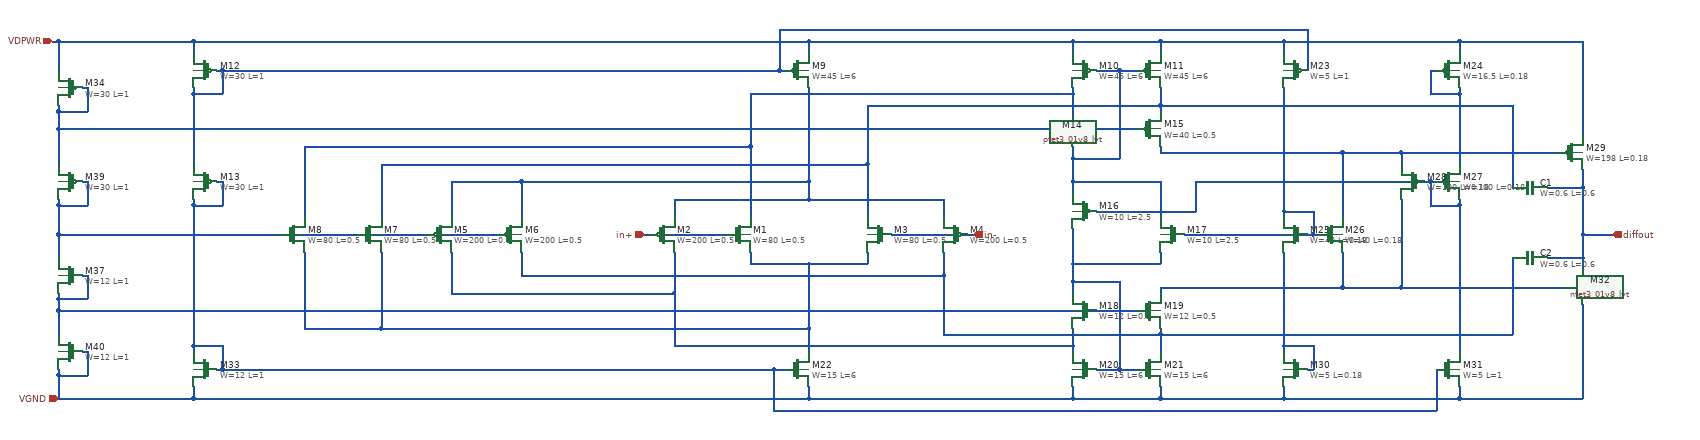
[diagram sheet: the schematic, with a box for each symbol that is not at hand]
v {xschem version=3.4.5 file_version=1.2
}
G {}
K {}
V {}
S {}
E {}
N -230 -60 -230 -30 {
lab=#net1}
N 0 -60 230 -60 {
lab=#net1}
N 230 -60 230 -30 {
lab=#net1}
N 0 -90 0 -60 {
lab=#net1}
N -490 -90 0 -90 {
lab=#net1}
N -490 -90 -490 -30 {
lab=#net1}
N -610 -90 -490 -90 {
lab=#net1}
N -610 -90 -610 -30 {
lab=#net1}
N -100 -150 -100 -30 {
lab=#net2}
N -860 -150 -100 -150 {
lab=#net2}
N -860 -150 -860 -30 {
lab=#net2}
N -730 -120 -730 -30 {
lab=#net3}
N -730 -120 100 -120 {
lab=#net3}
N 100 -120 100 -30 {
lab=#net3}
N -100 30 -100 50 {
lab=#net4}
N 0 50 0 160 {
lab=#net4}
N -730 160 0 160 {
lab=#net4}
N -730 30 -730 160 {
lab=#net4}
N -280 0 -140 0 {
lab=in+}
N -490 70 230 70 {
lab=#net5}
N 230 70 230 170 {
lab=#net5}
N -610 30 -610 100 {
lab=#net6}
N -610 100 -230 100 {
lab=#net6}
N -230 30 -230 100 {
lab=#net6}
N 0 -250 0 -90 {
lab=#net1}
N -1050 -250 -1050 -240 {
lab=#net7}
N -1050 -240 -1000 -240 {
lab=#net7}
N -1000 -280 -1000 -240 {
lab=#net7}
N -1050 -240 -1050 -120 {
lab=#net7}
N 530 -280 560 -280 {
lab=#net8}
N 450 -240 450 -200 {
lab=#net2}
N 600 -220 600 -210 {
lab=#net3}
N 450 -130 450 -90 {
lab=#net8}
N 530 -280 530 -130 {
lab=#net8}
N 450 50 450 80 {
lab=#net9}
N 450 -10 450 50 {
lab=#net9}
N 450 -90 600 -90 {
lab=#net8}
N 600 -90 600 -30 {
lab=#net8}
N 450 80 450 100 {
lab=#net9}
N 450 80 530 80 {
lab=#net9}
N 530 230 560 230 {
lab=#net9}
N 450 190 450 200 {
lab=#net6}
N 600 170 600 200 {
lab=#net5}
N 530 80 530 230 {
lab=#net9}
N 0 160 0 200 {
lab=#net4}
N 0 260 0 280 {
lab=VGND}
N 450 280 600 280 {
lab=VGND}
N 600 260 600 280 {
lab=VGND}
N 450 260 450 280 {
lab=VGND}
N 450 -330 450 -310 {
lab=VDPWR}
N 450 -330 600 -330 {
lab=VDPWR}
N 600 -330 600 -310 {
lab=VDPWR}
N 600 -330 810 -330 {
lab=VDPWR}
N 810 -330 810 -310 {
lab=VDPWR}
N 810 -330 1110 -330 {
lab=VDPWR}
N 1060 -280 1070 -280 {
lab=#net10}
N 1060 -280 1060 -240 {
lab=#net10}
N 1060 -240 1110 -240 {
lab=#net10}
N 1110 -250 1110 -240 {
lab=#net10}
N 810 -250 810 -40 {
lab=#net11}
N 860 0 870 0 {
lab=#net11}
N 860 -40 860 0 {
lab=#net11}
N 810 -40 860 -40 {
lab=#net11}
N 1060 -90 1070 -90 {
lab=#net12}
N 1110 -240 1110 -120 {
lab=#net10}
N 1060 -90 1060 -50 {
lab=#net12}
N 1060 -50 1110 -50 {
lab=#net12}
N 1110 -60 1110 -50 {
lab=#net12}
N 450 -130 530 -130 {
lab=#net8}
N 450 -90 450 -70 {
lab=#net8}
N 1110 -330 1110 -310 {
lab=VDPWR}
N 600 -150 600 -140 {
lab=#net13}
N 1010 -140 1280 -140 {
lab=#net13}
N -230 -60 0 -60 {
lab=#net1}
N -100 50 0 50 {
lab=#net4}
N -1010 -280 -1000 -280 {
lab=#net7}
N 490 -280 530 -280 {
lab=#net8}
N 490 230 530 230 {
lab=#net9}
N 0 280 450 280 {
lab=VGND}
N 450 -150 450 -130 {
lab=#net8}
N 810 -40 810 -30 {
lab=#net11}
N 600 30 600 50 {
lab=#net9}
N 450 50 600 50 {
lab=#net9}
N 490 -40 660 -40 {
lab=#net12}
N 660 -90 660 -40 {
lab=#net12}
N 640 0 860 0 {
lab=#net11}
N 660 -90 1060 -90 {
lab=#net12}
N 810 190 810 200 {
lab=#net14}
N 600 280 810 280 {
lab=VGND}
N 810 260 810 280 {
lab=VGND}
N 1110 -50 1110 200 {
lab=#net12}
N 1110 280 1320 280 {
lab=VGND}
N 1320 120 1320 280 {
lab=VGND}
N 1010 90 1290 90 {
lab=#net15}
N 1320 40 1320 60 {
lab=diffout}
N 1320 -330 1320 -170 {
lab=VDPWR}
N 1110 -330 1320 -330 {
lab=VDPWR}
N 1110 260 1110 280 {
lab=VGND}
N 1070 230 1070 300 {
lab=#net16}
N -60 300 1070 300 {
lab=#net16}
N -60 230 -60 300 {
lab=#net16}
N -60 230 -40 230 {
lab=#net16}
N -1000 230 -60 230 {
lab=#net16}
N -1050 260 -1050 280 {
lab=VGND}
N -1050 280 0 280 {
lab=VGND}
N -1000 190 -1000 230 {
lab=#net16}
N -1050 190 -1000 190 {
lab=#net16}
N -1050 190 -1050 200 {
lab=#net16}
N -1280 280 -1050 280 {
lab=VGND}
N 850 -350 850 -280 {
lab=#net7}
N -50 -350 850 -350 {
lab=#net7}
N 0 -330 0 -310 {
lab=VDPWR}
N 0 -330 450 -330 {
lab=VDPWR}
N -50 -350 -50 -280 {
lab=#net7}
N -50 -280 -40 -280 {
lab=#net7}
N -1050 -330 0 -330 {
lab=VDPWR}
N -1280 -330 -1280 -280 {
lab=VDPWR}
N -1050 -330 -1050 -310 {
lab=VDPWR}
N -1050 -50 -1000 -50 {
lab=#net16}
N -1000 -90 -1000 -50 {
lab=#net16}
N -1010 -90 -1000 -90 {
lab=#net16}
N 600 90 600 100 {
lab=#net15}
N 600 90 910 90 {
lab=#net15}
N 910 30 910 90 {
lab=#net15}
N 1010 -60 1010 90 {
lab=#net15}
N 850 230 860 230 {
lab=#net14}
N 860 190 860 230 {
lab=#net14}
N 810 190 860 190 {
lab=#net14}
N 600 170 1200 170 {
lab=#net5}
N 600 -220 1200 -220 {
lab=#net3}
N 1010 -140 1010 -120 {
lab=#net13}
N 910 -140 910 -30 {
lab=#net13}
N 140 0 280 0 {
lab=in-}
N 100 -220 100 -120 {
lab=#net3}
N 100 -220 600 -220 {
lab=#net3}
N -100 -240 -100 -150 {
lab=#net2}
N -100 -240 450 -240 {
lab=#net2}
N -230 100 -230 190 {
lab=#net6}
N -230 190 450 190 {
lab=#net6}
N -1280 -180 560 -180 {
lab=#net17}
N -1280 0 -530 0 {
lab=#net18}
N -1280 130 560 130 {
lab=#net19}
N 0 50 100 50 {
lab=#net4}
N 100 30 100 50 {
lab=#net4}
N -490 30 -490 70 {
lab=#net5}
N 230 30 230 70 {
lab=#net5}
N 810 280 1110 280 {
lab=VGND}
N -1010 230 -1000 230 {
lab=#net16}
N -1050 -50 -1050 190 {
lab=#net16}
N -1280 -330 -1050 -330 {
lab=VDPWR}
N -1050 -60 -1050 -50 {
lab=#net16}
N 910 90 1010 90 {
lab=#net15}
N 810 30 810 190 {
lab=#net14}
N 600 160 600 170 {
lab=#net5}
N 600 -250 600 -220 {
lab=#net3}
N 910 -140 1010 -140 {
lab=#net13}
N 600 -140 910 -140 {
lab=#net13}
N 450 -250 450 -240 {
lab=#net2}
N 450 160 450 190 {
lab=#net6}
N -860 30 -860 160 {
lab=#net4}
N -860 160 -730 160 {
lab=#net4}
N 1200 40 1200 170 {
lab=#net5}
N 1260 40 1320 40 {
lab=diffout}
N 1200 -220 1200 -80 {
lab=#net3}
N 1260 -80 1320 -80 {
lab=diffout}
N 1320 0 1370 0 {
lab=diffout}
N -1290 -330 -1280 -330 {
lab=VDPWR}
N -1000 -280 -50 -280 {
lab=#net7}
N -1240 -250 -1230 -250 {
lab=#net17}
N -1230 -250 -1230 -210 {
lab=#net17}
N -1280 -210 -1230 -210 {
lab=#net17}
N -1280 -220 -1280 -210 {
lab=#net17}
N -1280 -210 -1280 -180 {
lab=#net17}
N -1280 -180 -1280 -120 {
lab=#net17}
N -1240 -90 -1230 -90 {
lab=#net18}
N -1230 -90 -1230 -50 {
lab=#net18}
N -1280 -50 -1230 -50 {
lab=#net18}
N -1280 -60 -1280 -50 {
lab=#net18}
N -1280 -50 -1280 0 {
lab=#net18}
N -1240 70 -1230 70 {
lab=#net19}
N -1230 70 -1230 110 {
lab=#net19}
N -1280 110 -1230 110 {
lab=#net19}
N -1280 100 -1280 110 {
lab=#net19}
N -1280 0 -1280 40 {
lab=#net18}
N -1280 110 -1280 130 {
lab=#net19}
N -1240 200 -1230 200 {
lab=VGND}
N -1230 200 -1230 240 {
lab=VGND}
N -1280 240 -1230 240 {
lab=VGND}
N -1280 230 -1280 240 {
lab=VGND}
N -1280 130 -1280 170 {
lab=#net19}
N -1280 240 -1280 280 {
lab=VGND}
N 1320 0 1320 40 {
lab=diffout}
N 1320 -110 1320 -80 {
lab=diffout}
N 1320 -80 1320 0 {
lab=diffout}
N 230 170 600 170 {
lab=#net5}
C {sky130_fd_pr/nfet3_01v8_lvt.sym} -120 0 0 0 {name=M1
L=0.5
W=80
nf=4
mult=1
body=GND
ad="'int((nf+1)/2) * W/nf * 0.29'" 
pd="'2*int((nf+1)/2) * (W/nf + 0.29)'"
as="'int((nf+2)/2) * W/nf * 0.29'" 
ps="'2*int((nf+2)/2) * (W/nf + 0.29)'"
nrd="'0.29 / W'" nrs="'0.29 / W'"
sa=0 sb=0 sd=0
model=nfet_01v8_lvt
spiceprefix=X
}
C {sky130_fd_pr/pfet3_01v8_lvt.sym} -250 0 0 0 {name=M2
L=0.5
W=200
body=VDD
nf=6
mult=1
ad="'int((nf+1)/2) * W/nf * 0.29'" 
pd="'2*int((nf+1)/2) * (W/nf + 0.29)'"
as="'int((nf+2)/2) * W/nf * 0.29'" 
ps="'2*int((nf+2)/2) * (W/nf + 0.29)'"
nrd="'0.29 / W'" nrs="'0.29 / W'"
sa=0 sb=0 sd=0
model=pfet_01v8_lvt
spiceprefix=X
}
C {sky130_fd_pr/nfet3_01v8_lvt.sym} 120 0 0 1 {name=M3
L=0.5
W=80
nf=4
mult=1
body=GND
ad="'int((nf+1)/2) * W/nf * 0.29'" 
pd="'2*int((nf+1)/2) * (W/nf + 0.29)'"
as="'int((nf+2)/2) * W/nf * 0.29'" 
ps="'2*int((nf+2)/2) * (W/nf + 0.29)'"
nrd="'0.29 / W'" nrs="'0.29 / W'"
sa=0 sb=0 sd=0
model=nfet_01v8_lvt
spiceprefix=X
}
C {sky130_fd_pr/pfet3_01v8_lvt.sym} 250 0 0 1 {name=M4
L=0.5
W=200
body=VDD
nf=6
mult=1
ad="'int((nf+1)/2) * W/nf * 0.29'" 
pd="'2*int((nf+1)/2) * (W/nf + 0.29)'"
as="'int((nf+2)/2) * W/nf * 0.29'" 
ps="'2*int((nf+2)/2) * (W/nf + 0.29)'"
nrd="'0.29 / W'" nrs="'0.29 / W'"
sa=0 sb=0 sd=0
model=pfet_01v8_lvt
spiceprefix=X
}
C {sky130_fd_pr/pfet3_01v8_lvt.sym} -630 0 0 0 {name=M5
L=0.5
W=200
body=VDD
nf=6
mult=1
ad="'int((nf+1)/2) * W/nf * 0.29'" 
pd="'2*int((nf+1)/2) * (W/nf + 0.29)'"
as="'int((nf+2)/2) * W/nf * 0.29'" 
ps="'2*int((nf+2)/2) * (W/nf + 0.29)'"
nrd="'0.29 / W'" nrs="'0.29 / W'"
sa=0 sb=0 sd=0
model=pfet_01v8_lvt
spiceprefix=X
}
C {sky130_fd_pr/pfet3_01v8_lvt.sym} -510 0 0 0 {name=M6
L=0.5
W=200
body=VDD
nf=6
mult=1
ad="'int((nf+1)/2) * W/nf * 0.29'" 
pd="'2*int((nf+1)/2) * (W/nf + 0.29)'"
as="'int((nf+2)/2) * W/nf * 0.29'" 
ps="'2*int((nf+2)/2) * (W/nf + 0.29)'"
nrd="'0.29 / W'" nrs="'0.29 / W'"
sa=0 sb=0 sd=0
model=pfet_01v8_lvt
spiceprefix=X
}
C {sky130_fd_pr/nfet3_01v8_lvt.sym} -750 0 0 0 {name=M7
L=0.5
W=80
nf=1
mult=1
body=GND
ad="'int((nf+1)/2) * W/nf * 0.29'" 
pd="'2*int((nf+1)/2) * (W/nf + 0.29)'"
as="'int((nf+2)/2) * W/nf * 0.29'" 
ps="'2*int((nf+2)/2) * (W/nf + 0.29)'"
nrd="'0.29 / W'" nrs="'0.29 / W'"
sa=0 sb=0 sd=0
model=nfet_01v8_lvt
spiceprefix=X
}
C {sky130_fd_pr/nfet3_01v8_lvt.sym} -880 0 0 0 {name=M8
L=0.5
W=80
nf=1
mult=1
body=GND
ad="'int((nf+1)/2) * W/nf * 0.29'" 
pd="'2*int((nf+1)/2) * (W/nf + 0.29)'"
as="'int((nf+2)/2) * W/nf * 0.29'" 
ps="'2*int((nf+2)/2) * (W/nf + 0.29)'"
nrd="'0.29 / W'" nrs="'0.29 / W'"
sa=0 sb=0 sd=0
model=nfet_01v8_lvt
spiceprefix=X
}
C {devices/ipin.sym} -280 0 0 0 {name=p1 lab=in+}
C {devices/ipin.sym} 280 0 0 1 {name=p2 lab=in-

}
C {sky130_fd_pr/pfet3_01v8_lvt.sym} -20 -280 0 0 {name=M9
L=6
W=45
body=VDD
nf=1
mult=1
ad="'int((nf+1)/2) * W/nf * 0.29'" 
pd="'2*int((nf+1)/2) * (W/nf + 0.29)'"
as="'int((nf+2)/2) * W/nf * 0.29'" 
ps="'2*int((nf+2)/2) * (W/nf + 0.29)'"
nrd="'0.29 / W'" nrs="'0.29 / W'"
sa=0 sb=0 sd=0
model=pfet_01v8_lvt
spiceprefix=X
}
C {sky130_fd_pr/pfet3_01v8_lvt.sym} -1030 -280 0 1 {name=M12
L=1
W=30
body=VDD
nf=1
mult=1
ad="'int((nf+1)/2) * W/nf * 0.29'" 
pd="'2*int((nf+1)/2) * (W/nf + 0.29)'"
as="'int((nf+2)/2) * W/nf * 0.29'" 
ps="'2*int((nf+2)/2) * (W/nf + 0.29)'"
nrd="'0.29 / W'" nrs="'0.29 / W'"
sa=0 sb=0 sd=0
model=pfet_01v8_lvt
spiceprefix=X
}
C {sky130_fd_pr/pfet3_01v8_lvt.sym} -1030 -90 0 1 {name=M13
L=1
W=30
body=VDD
nf=1
mult=1
ad="'int((nf+1)/2) * W/nf * 0.29'" 
pd="'2*int((nf+1)/2) * (W/nf + 0.29)'"
as="'int((nf+2)/2) * W/nf * 0.29'" 
ps="'2*int((nf+2)/2) * (W/nf + 0.29)'"
nrd="'0.29 / W'" nrs="'0.29 / W'"
sa=0 sb=0 sd=0
model=pfet_01v8_lvt
spiceprefix=X
}
C {sky130_fd_pr/pfet3_01v8_lvt.sym} 470 -280 0 1 {name=M10
L=6
W=45
body=VDD
nf=1
mult=1
ad="'int((nf+1)/2) * W/nf * 0.29'" 
pd="'2*int((nf+1)/2) * (W/nf + 0.29)'"
as="'int((nf+2)/2) * W/nf * 0.29'" 
ps="'2*int((nf+2)/2) * (W/nf + 0.29)'"
nrd="'0.29 / W'" nrs="'0.29 / W'"
sa=0 sb=0 sd=0
model=pfet_01v8_lvt
spiceprefix=X
}
C {sky130_fd_pr/pfet3_01v8_lvt.sym} 580 -280 0 0 {name=M11
L=6
W=45
body=VDD
nf=1
mult=1
ad="'int((nf+1)/2) * W/nf * 0.29'" 
pd="'2*int((nf+1)/2) * (W/nf + 0.29)'"
as="'int((nf+2)/2) * W/nf * 0.29'" 
ps="'2*int((nf+2)/2) * (W/nf + 0.29)'"
nrd="'0.29 / W'" nrs="'0.29 / W'"
sa=0 sb=0 sd=0
model=pfet_01v8_lvt
spiceprefix=X
}
C {sky130_fd_pr/pfet3_01v8_lvt.sym} 470 -180 0 1 {name=M14
L=0.5
W=40
body=VDD
nf=1
mult=1
ad="'int((nf+1)/2) * W/nf * 0.29'" 
pd="'2*int((nf+1)/2) * (W/nf + 0.29)'"
as="'int((nf+2)/2) * W/nf * 0.29'" 
ps="'2*int((nf+2)/2) * (W/nf + 0.29)'"
nrd="'0.29 / W'" nrs="'0.29 / W'"
sa=0 sb=0 sd=0
model=pfet_01v8_lvt
spiceprefix=X
}
C {sky130_fd_pr/pfet3_01v8_lvt.sym} 580 -180 0 0 {name=M15
L=0.5
W=40
body=VDD
nf=1
mult=1
ad="'int((nf+1)/2) * W/nf * 0.29'" 
pd="'2*int((nf+1)/2) * (W/nf + 0.29)'"
as="'int((nf+2)/2) * W/nf * 0.29'" 
ps="'2*int((nf+2)/2) * (W/nf + 0.29)'"
nrd="'0.29 / W'" nrs="'0.29 / W'"
sa=0 sb=0 sd=0
model=pfet_01v8_lvt
spiceprefix=X
}
C {sky130_fd_pr/pfet3_01v8_lvt.sym} 470 -40 0 1 {name=M16
L=2.5
W=10
body=VDD
nf=1
mult=1
ad="'int((nf+1)/2) * W/nf * 0.29'" 
pd="'2*int((nf+1)/2) * (W/nf + 0.29)'"
as="'int((nf+2)/2) * W/nf * 0.29'" 
ps="'2*int((nf+2)/2) * (W/nf + 0.29)'"
nrd="'0.29 / W'" nrs="'0.29 / W'"
sa=0 sb=0 sd=0
model=pfet_01v8_lvt
spiceprefix=X
}
C {sky130_fd_pr/nfet3_01v8_lvt.sym} 620 0 0 1 {name=M17
L=2.5
W=10
nf=1
mult=1
body=GND
ad="'int((nf+1)/2) * W/nf * 0.29'" 
pd="'2*int((nf+1)/2) * (W/nf + 0.29)'"
as="'int((nf+2)/2) * W/nf * 0.29'" 
ps="'2*int((nf+2)/2) * (W/nf + 0.29)'"
nrd="'0.29 / W'" nrs="'0.29 / W'"
sa=0 sb=0 sd=0
model=nfet_01v8_lvt
spiceprefix=X
}
C {sky130_fd_pr/nfet3_01v8_lvt.sym} 470 130 0 1 {name=M18
L=0.5
W=12
nf=1
mult=1
body=GND
ad="'int((nf+1)/2) * W/nf * 0.29'" 
pd="'2*int((nf+1)/2) * (W/nf + 0.29)'"
as="'int((nf+2)/2) * W/nf * 0.29'" 
ps="'2*int((nf+2)/2) * (W/nf + 0.29)'"
nrd="'0.29 / W'" nrs="'0.29 / W'"
sa=0 sb=0 sd=0
model=nfet_01v8_lvt
spiceprefix=X
}
C {sky130_fd_pr/nfet3_01v8_lvt.sym} 580 130 0 0 {name=M19
L=0.5
W=12
nf=1
mult=1
body=GND
ad="'int((nf+1)/2) * W/nf * 0.29'" 
pd="'2*int((nf+1)/2) * (W/nf + 0.29)'"
as="'int((nf+2)/2) * W/nf * 0.29'" 
ps="'2*int((nf+2)/2) * (W/nf + 0.29)'"
nrd="'0.29 / W'" nrs="'0.29 / W'"
sa=0 sb=0 sd=0
model=nfet_01v8_lvt
spiceprefix=X
}
C {sky130_fd_pr/nfet3_01v8_lvt.sym} 470 230 0 1 {name=M20
L=6
W=15
nf=1
mult=1
body=GND
ad="'int((nf+1)/2) * W/nf * 0.29'" 
pd="'2*int((nf+1)/2) * (W/nf + 0.29)'"
as="'int((nf+2)/2) * W/nf * 0.29'" 
ps="'2*int((nf+2)/2) * (W/nf + 0.29)'"
nrd="'0.29 / W'" nrs="'0.29 / W'"
sa=0 sb=0 sd=0
model=nfet_01v8_lvt
spiceprefix=X
}
C {sky130_fd_pr/nfet3_01v8_lvt.sym} 580 230 0 0 {name=M21
L=6
W=15
nf=1
mult=1
body=GND
ad="'int((nf+1)/2) * W/nf * 0.29'" 
pd="'2*int((nf+1)/2) * (W/nf + 0.29)'"
as="'int((nf+2)/2) * W/nf * 0.29'" 
ps="'2*int((nf+2)/2) * (W/nf + 0.29)'"
nrd="'0.29 / W'" nrs="'0.29 / W'"
sa=0 sb=0 sd=0
model=nfet_01v8_lvt
spiceprefix=X
}
C {sky130_fd_pr/nfet3_01v8_lvt.sym} -20 230 0 0 {name=M22
L=6
W=15
nf=1
mult=1
body=GND
ad="'int((nf+1)/2) * W/nf * 0.29'" 
pd="'2*int((nf+1)/2) * (W/nf + 0.29)'"
as="'int((nf+2)/2) * W/nf * 0.29'" 
ps="'2*int((nf+2)/2) * (W/nf + 0.29)'"
nrd="'0.29 / W'" nrs="'0.29 / W'"
sa=0 sb=0 sd=0
model=nfet_01v8_lvt
spiceprefix=X
}
C {sky130_fd_pr/pfet3_01v8_lvt.sym} 830 -280 0 1 {name=M23
L=1
W=5
body=VDD
nf=1
mult=1
ad="'int((nf+1)/2) * W/nf * 0.29'" 
pd="'2*int((nf+1)/2) * (W/nf + 0.29)'"
as="'int((nf+2)/2) * W/nf * 0.29'" 
ps="'2*int((nf+2)/2) * (W/nf + 0.29)'"
nrd="'0.29 / W'" nrs="'0.29 / W'"
sa=0 sb=0 sd=0
model=pfet_01v8_lvt
spiceprefix=X
}
C {sky130_fd_pr/pfet3_01v8_lvt.sym} 1090 -280 0 0 {name=M24
L=0.18
W=16.5
body=VDD
nf=1
mult=1
ad="'int((nf+1)/2) * W/nf * 0.29'" 
pd="'2*int((nf+1)/2) * (W/nf + 0.29)'"
as="'int((nf+2)/2) * W/nf * 0.29'" 
ps="'2*int((nf+2)/2) * (W/nf + 0.29)'"
nrd="'0.29 / W'" nrs="'0.29 / W'"
sa=0 sb=0 sd=0
model=pfet_01v8_lvt
spiceprefix=X
}
C {sky130_fd_pr/nfet3_01v8_lvt.sym} 830 0 0 1 {name=M25
L=0.18
W=40
nf=1
mult=1
body=GND
ad="'int((nf+1)/2) * W/nf * 0.29'" 
pd="'2*int((nf+1)/2) * (W/nf + 0.29)'"
as="'int((nf+2)/2) * W/nf * 0.29'" 
ps="'2*int((nf+2)/2) * (W/nf + 0.29)'"
nrd="'0.29 / W'" nrs="'0.29 / W'"
sa=0 sb=0 sd=0
model=nfet_01v8_lvt
spiceprefix=X
}
C {sky130_fd_pr/nfet3_01v8_lvt.sym} 890 0 0 0 {name=M26
L=0.18
W=40
nf=1
mult=1
body=GND
ad="'int((nf+1)/2) * W/nf * 0.29'" 
pd="'2*int((nf+1)/2) * (W/nf + 0.29)'"
as="'int((nf+2)/2) * W/nf * 0.29'" 
ps="'2*int((nf+2)/2) * (W/nf + 0.29)'"
nrd="'0.29 / W'" nrs="'0.29 / W'"
sa=0 sb=0 sd=0
model=nfet_01v8_lvt
spiceprefix=X
}
C {sky130_fd_pr/pfet3_01v8_lvt.sym} 1090 -90 0 0 {name=M27
L=0.18
W=100
body=VDD
nf=1
mult=1
ad="'int((nf+1)/2) * W/nf * 0.29'" 
pd="'2*int((nf+1)/2) * (W/nf + 0.29)'"
as="'int((nf+2)/2) * W/nf * 0.29'" 
ps="'2*int((nf+2)/2) * (W/nf + 0.29)'"
nrd="'0.29 / W'" nrs="'0.29 / W'"
sa=0 sb=0 sd=0
model=pfet_01v8_lvt
spiceprefix=X
}
C {sky130_fd_pr/pfet3_01v8_lvt.sym} 1030 -90 0 1 {name=M28
L=0.18
W=100
body=VDD
nf=1
mult=1
ad="'int((nf+1)/2) * W/nf * 0.29'" 
pd="'2*int((nf+1)/2) * (W/nf + 0.29)'"
as="'int((nf+2)/2) * W/nf * 0.29'" 
ps="'2*int((nf+2)/2) * (W/nf + 0.29)'"
nrd="'0.29 / W'" nrs="'0.29 / W'"
sa=0 sb=0 sd=0
model=pfet_01v8_lvt
spiceprefix=X
}
C {sky130_fd_pr/pfet3_01v8_lvt.sym} 1300 -140 0 0 {name=M29
L=0.18
W=198
body=VDD
nf=18
mult=1
ad="'int((nf+1)/2) * W/nf * 0.29'" 
pd="'2*int((nf+1)/2) * (W/nf + 0.29)'"
as="'int((nf+2)/2) * W/nf * 0.29'" 
ps="'2*int((nf+2)/2) * (W/nf + 0.29)'"
nrd="'0.29 / W'" nrs="'0.29 / W'"
sa=0 sb=0 sd=0
model=pfet_01v8_lvt
spiceprefix=X
}
C {sky130_fd_pr/nfet3_01v8_lvt.sym} 830 230 0 1 {name=M30
L=0.18
W=5
nf=1
mult=1
body=GND
ad="'int((nf+1)/2) * W/nf * 0.29'" 
pd="'2*int((nf+1)/2) * (W/nf + 0.29)'"
as="'int((nf+2)/2) * W/nf * 0.29'" 
ps="'2*int((nf+2)/2) * (W/nf + 0.29)'"
nrd="'0.29 / W'" nrs="'0.29 / W'"
sa=0 sb=0 sd=0
model=nfet_01v8_lvt
spiceprefix=X
}
C {sky130_fd_pr/nfet3_01v8_lvt.sym} 1090 230 0 0 {name=M31
L=1
W=5
nf=1
mult=1
body=GND
ad="'int((nf+1)/2) * W/nf * 0.29'" 
pd="'2*int((nf+1)/2) * (W/nf + 0.29)'"
as="'int((nf+2)/2) * W/nf * 0.29'" 
ps="'2*int((nf+2)/2) * (W/nf + 0.29)'"
nrd="'0.29 / W'" nrs="'0.29 / W'"
sa=0 sb=0 sd=0
model=nfet_01v8_lvt
spiceprefix=X
}
C {sky130_fd_pr/nfet3_01v8_lvt.sym} 1310 90 0 0 {name=M32
L=0.18
W=60
nf=10
mult=1
body=GND
ad="'int((nf+1)/2) * W/nf * 0.29'" 
pd="'2*int((nf+1)/2) * (W/nf + 0.29)'"
as="'int((nf+2)/2) * W/nf * 0.29'" 
ps="'2*int((nf+2)/2) * (W/nf + 0.29)'"
nrd="'0.29 / W'" nrs="'0.29 / W'"
sa=0 sb=0 sd=0
model=nfet_01v8_lvt
spiceprefix=X
}
C {sky130_fd_pr/nfet3_01v8_lvt.sym} -1030 230 0 1 {name=M33
L=1
W=12

mult=1
body=GND
ad="'int((nf+1)/2) * W/nf * 0.29'" 
pd="'2*int((nf+1)/2) * (W/nf + 0.29)'"
as="'int((nf+2)/2) * W/nf * 0.29'" 
ps="'2*int((nf+2)/2) * (W/nf + 0.29)'"
nrd="'0.29 / W'" nrs="'0.29 / W'"
sa=0 sb=0 sd=0
model=nfet_01v8_lvt
spiceprefix=X
nf=1}
C {sky130_fd_pr/cap_mim_m3_1.sym} 1230 -80 1 0 {name=C1 model=cap_mim_m3_1 W=0.6 L=0.6 MF=1 spiceprefix=X}
C {sky130_fd_pr/cap_mim_m3_1.sym} 1230 40 1 0 {name=C2 model=cap_mim_m3_1 W=0.6 L=0.6 MF=1 spiceprefix=X}
C {devices/opin.sym} 1370 0 0 0 {name=p3 lab=diffout}
C {devices/ipin.sym} -1290 -330 0 0 {name=p4 lab=VDPWR}
C {devices/ipin.sym} -1280 280 0 0 {name=p5 lab=VGND}
C {sky130_fd_pr/pfet3_01v8_lvt.sym} -1260 -250 0 1 {name=M34
L=1
W=30
body=VDD
nf=1
mult=1
ad="'int((nf+1)/2) * W/nf * 0.29'" 
pd="'2*int((nf+1)/2) * (W/nf + 0.29)'"
as="'int((nf+2)/2) * W/nf * 0.29'" 
ps="'2*int((nf+2)/2) * (W/nf + 0.29)'"
nrd="'0.29 / W'" nrs="'0.29 / W'"
sa=0 sb=0 sd=0
model=pfet_01v8_lvt
spiceprefix=X
}
C {sky130_fd_pr/nfet3_01v8_lvt.sym} -1260 70 0 1 {name=M37
L=1
W=12

mult=1
body=GND
ad="'int((nf+1)/2) * W/nf * 0.29'" 
pd="'2*int((nf+1)/2) * (W/nf + 0.29)'"
as="'int((nf+2)/2) * W/nf * 0.29'" 
ps="'2*int((nf+2)/2) * (W/nf + 0.29)'"
nrd="'0.29 / W'" nrs="'0.29 / W'"
sa=0 sb=0 sd=0
model=nfet_01v8_lvt
spiceprefix=X
nf=1}
C {sky130_fd_pr/pfet3_01v8_lvt.sym} -1260 -90 0 1 {name=M39
L=1
W=30
body=VDD
nf=1
mult=1
ad="'int((nf+1)/2) * W/nf * 0.29'" 
pd="'2*int((nf+1)/2) * (W/nf + 0.29)'"
as="'int((nf+2)/2) * W/nf * 0.29'" 
ps="'2*int((nf+2)/2) * (W/nf + 0.29)'"
nrd="'0.29 / W'" nrs="'0.29 / W'"
sa=0 sb=0 sd=0
model=pfet_01v8_lvt
spiceprefix=X
}
C {sky130_fd_pr/nfet3_01v8_lvt.sym} -1260 200 0 1 {name=M40
L=1
W=12

mult=1
body=GND
ad="'int((nf+1)/2) * W/nf * 0.29'" 
pd="'2*int((nf+1)/2) * (W/nf + 0.29)'"
as="'int((nf+2)/2) * W/nf * 0.29'" 
ps="'2*int((nf+2)/2) * (W/nf + 0.29)'"
nrd="'0.29 / W'" nrs="'0.29 / W'"
sa=0 sb=0 sd=0
model=nfet_01v8_lvt
spiceprefix=X
nf=1}
